VERSION 5.7 ;
BUSBITCHARS "[]" ;
DIVIDERCHAR "/" ;

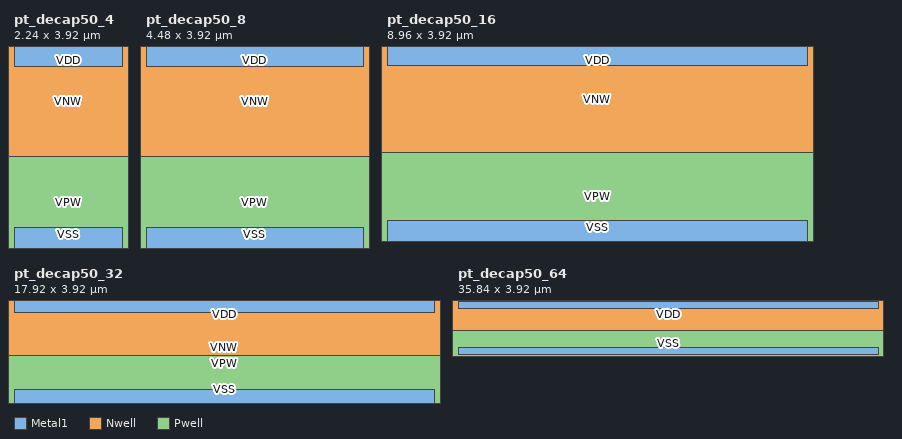
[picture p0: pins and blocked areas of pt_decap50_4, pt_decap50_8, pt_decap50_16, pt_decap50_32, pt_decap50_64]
MACRO pt_decap50_4
  CLASS CORE SPACER ;
  FOREIGN pt_decap50_4 ;
  ORIGIN 0.000 0.000 ;
  SIZE 2.240 BY 3.920 ;
  SYMMETRY X Y ;
  SITE GF018hv5v_mcu_sc7 ;
  PIN VDD
    DIRECTION INOUT ;
    USE POWER ;
    SHAPE ABUTMENT ;
    PORT
      LAYER Metal1 ;
        RECT 0.000 3.620 2.240 4.220 ;
    END
  END VDD
  PIN VNW
    DIRECTION INOUT ;
    USE POWER ;
    PORT
      LAYER Nwell ;
        RECT -0.430 1.760 2.670 4.350 ;
    END
  END VNW
  PIN VPW
    DIRECTION INOUT ;
    USE GROUND ;
    PORT
      LAYER Pwell ;
        RECT -0.430 -0.430 2.670 1.760 ;
    END
  END VPW
  PIN VSS
    DIRECTION INOUT ;
    USE GROUND ;
    SHAPE ABUTMENT ;
    PORT
      LAYER Metal1 ;
        RECT 0.000 -0.300 2.240 0.300 ;
    END
  END VSS
  OBS
      LAYER Metal1 ;
        RECT 0.190 0.300 2.050 3.620 ;
  END
END pt_decap50_4

MACRO pt_decap50_8
  CLASS CORE SPACER ;
  FOREIGN pt_decap50_8 ;
  ORIGIN 0.000 0.000 ;
  SIZE 4.480 BY 3.920 ;
  SYMMETRY X Y ;
  SITE GF018hv5v_mcu_sc7 ;
  PIN VDD
    DIRECTION INOUT ;
    USE POWER ;
    SHAPE ABUTMENT ;
    PORT
      LAYER Metal1 ;
        RECT 0.000 3.620 4.480 4.220 ;
    END
  END VDD
  PIN VNW
    DIRECTION INOUT ;
    USE POWER ;
    PORT
      LAYER Nwell ;
        RECT -0.430 1.760 4.910 4.350 ;
    END
  END VNW
  PIN VPW
    DIRECTION INOUT ;
    USE GROUND ;
    PORT
      LAYER Pwell ;
        RECT -0.430 -0.430 4.910 1.760 ;
    END
  END VPW
  PIN VSS
    DIRECTION INOUT ;
    USE GROUND ;
    SHAPE ABUTMENT ;
    PORT
      LAYER Metal1 ;
        RECT 0.000 -0.300 4.480 0.300 ;
    END
  END VSS
  OBS
      LAYER Metal1 ;
        RECT 0.190 0.300 4.290 3.620 ;
  END
END pt_decap50_8

MACRO pt_decap50_16
  CLASS CORE SPACER ;
  FOREIGN pt_decap50_16 ;
  ORIGIN 0.000 0.000 ;
  SIZE 8.960 BY 3.920 ;
  SYMMETRY X Y ;
  SITE GF018hv5v_mcu_sc7 ;
  PIN VDD
    DIRECTION INOUT ;
    USE POWER ;
    SHAPE ABUTMENT ;
    PORT
      LAYER Metal1 ;
        RECT 0.000 3.620 8.960 4.220 ;
    END
  END VDD
  PIN VNW
    DIRECTION INOUT ;
    USE POWER ;
    PORT
      LAYER Nwell ;
        RECT -0.430 1.760 9.390 4.350 ;
    END
  END VNW
  PIN VPW
    DIRECTION INOUT ;
    USE GROUND ;
    PORT
      LAYER Pwell ;
        RECT -0.430 -0.430 9.390 1.760 ;
    END
  END VPW
  PIN VSS
    DIRECTION INOUT ;
    USE GROUND ;
    SHAPE ABUTMENT ;
    PORT
      LAYER Metal1 ;
        RECT 0.000 -0.300 8.960 0.300 ;
    END
  END VSS
  OBS
      LAYER Metal1 ;
        RECT 0.190 0.300 8.770 3.620 ;
  END
END pt_decap50_16

MACRO pt_decap50_32
  CLASS CORE SPACER ;
  FOREIGN pt_decap50_32 ;
  ORIGIN 0.000 0.000 ;
  SIZE 17.920 BY 3.920 ;
  SYMMETRY X Y ;
  SITE GF018hv5v_mcu_sc7 ;
  PIN VDD
    DIRECTION INOUT ;
    USE POWER ;
    SHAPE ABUTMENT ;
    PORT
      LAYER Metal1 ;
        RECT 0.000 3.620 17.920 4.220 ;
    END
  END VDD
  PIN VNW
    DIRECTION INOUT ;
    USE POWER ;
    PORT
      LAYER Nwell ;
        RECT -0.430 1.760 18.350 4.350 ;
    END
  END VNW
  PIN VPW
    DIRECTION INOUT ;
    USE GROUND ;
    PORT
      LAYER Pwell ;
        RECT -0.430 -0.430 18.350 1.760 ;
    END
  END VPW
  PIN VSS
    DIRECTION INOUT ;
    USE GROUND ;
    SHAPE ABUTMENT ;
    PORT
      LAYER Metal1 ;
        RECT 0.000 -0.300 17.920 0.300 ;
    END
  END VSS
  OBS
      LAYER Metal1 ;
        RECT 0.190 0.300 17.730 3.620 ;
  END
END pt_decap50_32

MACRO pt_decap50_64
  CLASS CORE SPACER ;
  FOREIGN pt_decap50_64 ;
  ORIGIN 0.000 0.000 ;
  SIZE 35.840 BY 3.920 ;
  SYMMETRY X Y ;
  SITE GF018hv5v_mcu_sc7 ;
  PIN VDD
    DIRECTION INOUT ;
    USE POWER ;
    SHAPE ABUTMENT ;
    PORT
      LAYER Metal1 ;
        RECT 0.000 3.620 35.840 4.220 ;
    END
  END VDD
  PIN VNW
    DIRECTION INOUT ;
    USE POWER ;
    PORT
      LAYER Nwell ;
        RECT -0.430 1.760 36.270 4.350 ;
    END
  END VNW
  PIN VPW
    DIRECTION INOUT ;
    USE GROUND ;
    PORT
      LAYER Pwell ;
        RECT -0.430 -0.430 36.270 1.760 ;
    END
  END VPW
  PIN VSS
    DIRECTION INOUT ;
    USE GROUND ;
    SHAPE ABUTMENT ;
    PORT
      LAYER Metal1 ;
        RECT 0.000 -0.300 35.840 0.300 ;
    END
  END VSS
  OBS
      LAYER Metal1 ;
        RECT 0.190 0.300 35.650 3.620 ;
  END
END pt_decap50_64

END LIBRARY
